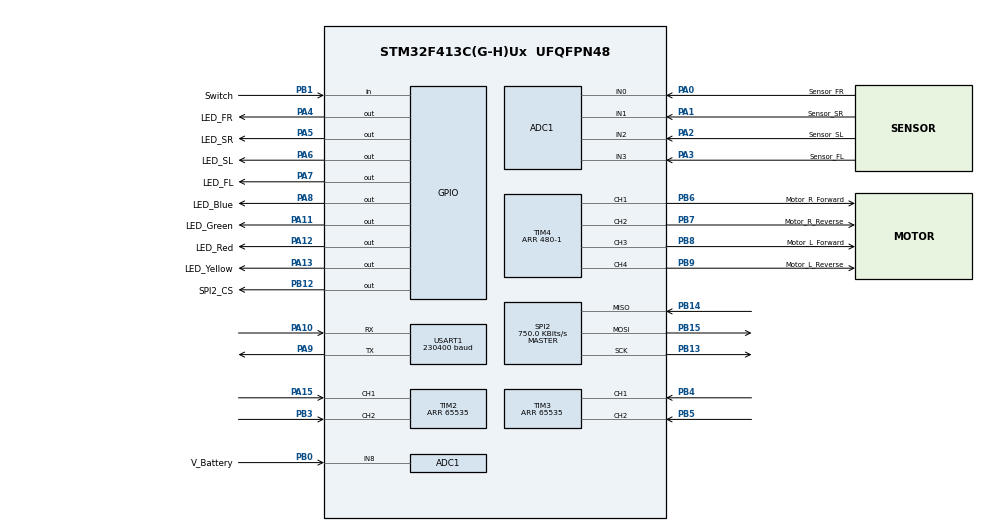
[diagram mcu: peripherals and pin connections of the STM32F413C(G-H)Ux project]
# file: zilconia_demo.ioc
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ADC1.Channel-4\#ChannelRegularConversion=ADC_CHANNEL_8
ADC1.Channel-5\#ChannelRegularConversion=ADC_CHANNEL_0
ADC1.Channel-6\#ChannelRegularConversion=ADC_CHANNEL_1
ADC1.Channel-7\#ChannelRegularConversion=ADC_CHANNEL_2
ADC1.Channel-8\#ChannelRegularConversion=ADC_CHANNEL_3
ADC1.ClockPrescaler=ADC_CLOCK_SYNC_PCLK_DIV4
ADC1.DMAContinuousRequests=ENABLE
ADC1.EOCSelection=ADC_EOC_SEQ_CONV
ADC1.ExternalTrigConv=ADC_EXTERNALTRIGCONV_T1_CC3
ADC1.InjNumberOfConversion=0
ADC1.NbrOfConversion=5
ADC1.NbrOfConversionFlag=1
ADC1.Rank-4\#ChannelRegularConversion=1
ADC1.Rank-5\#ChannelRegularConversion=2
ADC1.Rank-6\#ChannelRegularConversion=3
ADC1.Rank-7\#ChannelRegularConversion=4
ADC1.Rank-8\#ChannelRegularConversion=5
ADC1.SamplingTime-4\#ChannelRegularConversion=ADC_SAMPLETIME_56CYCLES
ADC1.SamplingTime-5\#ChannelRegularConversion=ADC_SAMPLETIME_56CYCLES
ADC1.SamplingTime-6\#ChannelRegularConversion=ADC_SAMPLETIME_56CYCLES
ADC1.SamplingTime-7\#ChannelRegularConversion=ADC_SAMPLETIME_56CYCLES
ADC1.SamplingTime-8\#ChannelRegularConversion=ADC_SAMPLETIME_56CYCLES
ADC1.ScanConvMode=ENABLE
ADC1.master=1
Dma.ADC1.0.Direction=DMA_PERIPH_TO_MEMORY
Dma.ADC1.0.FIFOMode=DMA_FIFOMODE_DISABLE
Dma.ADC1.0.Instance=DMA2_Stream0
Dma.ADC1.0.MemDataAlignment=DMA_MDATAALIGN_HALFWORD
Dma.ADC1.0.MemInc=DMA_MINC_ENABLE
Dma.ADC1.0.Mode=DMA_CIRCULAR
Dma.ADC1.0.PeriphDataAlignment=DMA_PDATAALIGN_HALFWORD
Dma.ADC1.0.PeriphInc=DMA_PINC_DISABLE
Dma.ADC1.0.Priority=DMA_PRIORITY_VERY_HIGH
Dma.Request0=ADC1
Dma.Request1=SPI2_RX
Dma.Request2=SPI2_TX
Dma.Request3=TIM1_CH1
Dma.Request4=TIM1_CH2
Dma.Request5=USART1_RX
Dma.Request6=USART1_TX
Dma.SPI2_RX.1.Direction=DMA_PERIPH_TO_MEMORY
Dma.SPI2_RX.1.FIFOMode=DMA_FIFOMODE_DISABLE
Dma.SPI2_RX.1.Instance=DMA1_Stream3
Dma.SPI2_RX.1.MemDataAlignment=DMA_MDATAALIGN_BYTE
Dma.SPI2_RX.1.MemInc=DMA_MINC_ENABLE
Dma.SPI2_RX.1.Mode=DMA_NORMAL
Dma.SPI2_RX.1.PeriphDataAlignment=DMA_PDATAALIGN_BYTE
Dma.SPI2_RX.1.PeriphInc=DMA_PINC_DISABLE
Dma.SPI2_RX.1.Priority=DMA_PRIORITY_VERY_HIGH
Dma.SPI2_TX.2.Direction=DMA_MEMORY_TO_PERIPH
Dma.SPI2_TX.2.FIFOMode=DMA_FIFOMODE_DISABLE
Dma.SPI2_TX.2.Instance=DMA1_Stream4
Dma.SPI2_TX.2.MemDataAlignment=DMA_MDATAALIGN_BYTE
Dma.SPI2_TX.2.MemInc=DMA_MINC_ENABLE
Dma.SPI2_TX.2.Mode=DMA_NORMAL
Dma.SPI2_TX.2.PeriphDataAlignment=DMA_PDATAALIGN_BYTE
Dma.SPI2_TX.2.PeriphInc=DMA_PINC_DISABLE
Dma.SPI2_TX.2.Priority=DMA_PRIORITY_VERY_HIGH
Dma.TIM1_CH1.3.Direction=DMA_MEMORY_TO_PERIPH
Dma.TIM1_CH1.3.FIFOMode=DMA_FIFOMODE_DISABLE
Dma.TIM1_CH1.3.Instance=DMA2_Stream1
Dma.TIM1_CH1.3.MemDataAlignment=DMA_MDATAALIGN_HALFWORD
Dma.TIM1_CH1.3.MemInc=DMA_MINC_ENABLE
Dma.TIM1_CH1.3.Mode=DMA_CIRCULAR
Dma.TIM1_CH1.3.PeriphDataAlignment=DMA_PDATAALIGN_HALFWORD
Dma.TIM1_CH1.3.PeriphInc=DMA_PINC_DISABLE
Dma.TIM1_CH1.3.Priority=DMA_PRIORITY_VERY_HIGH
Dma.TIM1_CH2.4.Direction=DMA_MEMORY_TO_PERIPH
Dma.TIM1_CH2.4.FIFOMode=DMA_FIFOMODE_DISABLE
Dma.TIM1_CH2.4.Instance=DMA2_Stream2
Dma.TIM1_CH2.4.MemDataAlignment=DMA_MDATAALIGN_HALFWORD
Dma.TIM1_CH2.4.MemInc=DMA_MINC_ENABLE
Dma.TIM1_CH2.4.Mode=DMA_CIRCULAR
Dma.TIM1_CH2.4.PeriphDataAlignment=DMA_PDATAALIGN_HALFWORD
Dma.TIM1_CH2.4.PeriphInc=DMA_PINC_DISABLE
Dma.TIM1_CH2.4.Priority=DMA_PRIORITY_VERY_HIGH
Dma.USART1_RX.5.Direction=DMA_PERIPH_TO_MEMORY
Dma.USART1_RX.5.FIFOMode=DMA_FIFOMODE_DISABLE
Dma.USART1_RX.5.Instance=DMA2_Stream5
Dma.USART1_RX.5.MemDataAlignment=DMA_MDATAALIGN_BYTE
Dma.USART1_RX.5.MemInc=DMA_MINC_ENABLE
Dma.USART1_RX.5.Mode=DMA_CIRCULAR
Dma.USART1_RX.5.PeriphDataAlignment=DMA_PDATAALIGN_BYTE
Dma.USART1_RX.5.PeriphInc=DMA_PINC_DISABLE
Dma.USART1_RX.5.Priority=DMA_PRIORITY_LOW
Dma.USART1_TX.6.Direction=DMA_MEMORY_TO_PERIPH
Dma.USART1_TX.6.FIFOMode=DMA_FIFOMODE_DISABLE
Dma.USART1_TX.6.Instance=DMA2_Stream7
Dma.USART1_TX.6.MemDataAlignment=DMA_MDATAALIGN_BYTE
Dma.USART1_TX.6.MemInc=DMA_MINC_ENABLE
Dma.USART1_TX.6.Mode=DMA_NORMAL
Dma.USART1_TX.6.PeriphDataAlignment=DMA_PDATAALIGN_BYTE
Dma.USART1_TX.6.PeriphInc=DMA_PINC_DISABLE
Dma.USART1_TX.6.Priority=DMA_PRIORITY_LOW
Mcu.Family=STM32F4
Mcu.Name=STM32F413C(G-H)Ux
Mcu.Package=UFQFPN48
NVIC.DMA1_Stream3_IRQn=true\:0\:0\:false\:false\:true\:false\:true
NVIC.DMA1_Stream4_IRQn=true\:0\:0\:false\:false\:true\:false\:true
NVIC.DMA2_Stream0_IRQn=true\:0\:0\:false\:false\:true\:false\:true
NVIC.DMA2_Stream1_IRQn=true\:0\:0\:false\:false\:true\:false\:true
NVIC.DMA2_Stream2_IRQn=true\:0\:0\:false\:false\:true\:false\:true
NVIC.DMA2_Stream5_IRQn=true\:2\:0\:true\:false\:true\:false\:true
NVIC.DMA2_Stream7_IRQn=true\:2\:0\:true\:false\:true\:false\:true
NVIC.PriorityGroup=NVIC_PRIORITYGROUP_4
NVIC.TIM6_DAC_IRQn=true\:1\:0\:true\:false\:true\:true\:true
NVIC.USART1_IRQn=true\:2\:0\:true\:false\:true\:true\:true
PA0.GPIO_Label=Sensor_FR
PA0.Signal=ADCx_IN0
PA1.GPIO_Label=Sensor_SR
PA1.Signal=ADCx_IN1
PA10.Mode=Asynchronous
PA10.Signal=USART1_RX
PA11.GPIO_Label=LED_Green
PA11.GPIO_Speed=GPIO_SPEED_FREQ_HIGH
PA11.Signal=GPIO_Output
PA12.GPIO_Label=LED_Red
PA12.GPIO_Speed=GPIO_SPEED_FREQ_HIGH
PA12.Signal=GPIO_Output
PA13.GPIO_Label=LED_Yellow
PA13.GPIO_Speed=GPIO_SPEED_FREQ_HIGH
PA13.Signal=GPIO_Output
PA15.Signal=S_TIM2_CH1_ETR
PA2.GPIO_Label=Sensor_SL
PA2.Signal=ADCx_IN2
PA3.GPIO_Label=Sensor_FL
PA3.Signal=ADCx_IN3
PA4.GPIO_Label=LED_FR
PA4.GPIO_Speed=GPIO_SPEED_FREQ_HIGH
PA4.Signal=GPIO_Output
PA5.GPIO_Label=LED_SR
PA5.GPIO_Speed=GPIO_SPEED_FREQ_HIGH
PA5.Signal=GPIO_Output
PA6.GPIO_Label=LED_SL
PA6.GPIO_Speed=GPIO_SPEED_FREQ_HIGH
PA6.Signal=GPIO_Output
PA7.GPIO_Label=LED_FL
PA7.GPIO_Speed=GPIO_SPEED_FREQ_HIGH
PA7.Signal=GPIO_Output
PA8.GPIO_Label=LED_Blue
PA8.GPIO_Speed=GPIO_SPEED_FREQ_HIGH
PA8.Signal=GPIO_Output
PA9.Mode=Asynchronous
PA9.Signal=USART1_TX
PB0.GPIO_Label=V_Battery
PB0.Signal=ADCx_IN8
PB1.GPIO_Label=Switch
PB1.Signal=GPIO_Input
PB12.GPIO_Label=SPI2_CS
PB12.GPIO_Speed=GPIO_SPEED_FREQ_VERY_HIGH
PB12.Signal=GPIO_Output
PB13.Mode=Full_Duplex_Master
PB13.Signal=SPI2_SCK
PB14.Mode=Full_Duplex_Master
PB14.Signal=SPI2_MISO
PB15.Mode=Full_Duplex_Master
PB15.Signal=SPI2_MOSI
PB3.Signal=S_TIM2_CH2
PB4.Signal=S_TIM3_CH1
PB5.Signal=S_TIM3_CH2
PB6.GPIO_Label=Motor_R_Forward
PB6.GPIO_Speed=GPIO_SPEED_FREQ_VERY_HIGH
PB6.Signal=S_TIM4_CH1
PB7.GPIO_Label=Motor_R_Reverse
PB7.GPIO_Speed=GPIO_SPEED_FREQ_VERY_HIGH
PB7.Signal=S_TIM4_CH2
PB8.GPIO_Label=Motor_L_Forward
PB8.GPIO_Speed=GPIO_SPEED_FREQ_VERY_HIGH
PB8.Signal=S_TIM4_CH3
PB9.GPIO_Label=Motor_L_Reverse
PB9.GPIO_Speed=GPIO_SPEED_FREQ_VERY_HIGH
PB9.Signal=S_TIM4_CH4
ProjectManager.HeapSize=0x200
ProjectManager.StackSize=0x400
ProjectManager.TargetToolchain=TrueSTUDIO
RCC.AHBFreq_Value=96000000
RCC.APB1CLKDivider=RCC_HCLK_DIV2
RCC.APB1Freq_Value=48000000
RCC.APB1TimFreq_Value=96000000
RCC.APB2Freq_Value=96000000
RCC.APB2TimFreq_Value=96000000
RCC.CortexFreq_Value=96000000
RCC.HCLKFreq_Value=96000000
RCC.SYSCLKFreq_VALUE=96000000
RCC.SYSCLKSource=RCC_SYSCLKSOURCE_PLLCLK
RCC.USBFreq_Value=96000000
RCC.VCOOutputFreq_Value=192000000
SH.ADCx_IN0.0=ADC1_IN0,IN0
SH.ADCx_IN1.0=ADC1_IN1,IN1
SH.ADCx_IN2.0=ADC1_IN2,IN2
SH.ADCx_IN3.0=ADC1_IN3,IN3
SH.ADCx_IN8.0=ADC1_IN8,IN8
SH.S_TIM2_CH1_ETR.0=TIM2_CH1,Encoder_Interface
SH.S_TIM2_CH2.0=TIM2_CH2,Encoder_Interface
SH.S_TIM3_CH1.0=TIM3_CH1,Encoder_Interface
SH.S_TIM3_CH2.0=TIM3_CH2,Encoder_Interface
SH.S_TIM4_CH1.0=TIM4_CH1,PWM Generation1 CH1
SH.S_TIM4_CH2.0=TIM4_CH2,PWM Generation2 CH2
SH.S_TIM4_CH3.0=TIM4_CH3,PWM Generation3 CH3
SH.S_TIM4_CH4.0=TIM4_CH4,PWM Generation4 CH4
SPI2.BaudRatePrescaler=SPI_BAUDRATEPRESCALER_64
SPI2.CLKPhase=SPI_PHASE_2EDGE
SPI2.CLKPolarity=SPI_POLARITY_HIGH
SPI2.CalculateBaudRate=750.0 KBits/s
SPI2.Direction=SPI_DIRECTION_2LINES
SPI2.Mode=SPI_MODE_MASTER
SPI2.VirtualType=VM_MASTER
TIM1.Channel-PWM\ Generation1\ No\ Output=TIM_CHANNEL_1
TIM1.Channel-PWM\ Generation2\ No\ Output=TIM_CHANNEL_2
TIM1.Channel-PWM\ Generation3\ No\ Output=TIM_CHANNEL_3
TIM1.OCMode_PWM-PWM\ Generation1\ No\ Output=TIM_OCMODE_PWM1
TIM1.OCMode_PWM-PWM\ Generation2\ No\ Output=TIM_OCMODE_PWM1
TIM1.OCMode_PWM-PWM\ Generation3\ No\ Output=TIM_OCMODE_PWM1
TIM1.Period=32000-1
TIM1.Pulse-PWM\ Generation1\ No\ Output=2-1
TIM1.Pulse-PWM\ Generation2\ No\ Output=2402-1
TIM1.Pulse-PWM\ Generation3\ No\ Output=1922-1
TIM1.TIM_MasterOutputTrigger=TIM_TRGO_RESET
TIM1.TIM_MasterSlaveMode=TIM_MASTERSLAVEMODE_DISABLE
TIM2.EncoderMode=TIM_ENCODERMODE_TI12
TIM2.Period=65535
TIM3.EncoderMode=TIM_ENCODERMODE_TI12
TIM3.Period=65535
TIM4.Channel-PWM\ Generation1\ CH1=TIM_CHANNEL_1
TIM4.Channel-PWM\ Generation2\ CH2=TIM_CHANNEL_2
TIM4.Channel-PWM\ Generation3\ CH3=TIM_CHANNEL_3
TIM4.Channel-PWM\ Generation4\ CH4=TIM_CHANNEL_4
TIM4.OCMode_PWM-PWM\ Generation1\ CH1=TIM_OCMODE_PWM2
TIM4.OCMode_PWM-PWM\ Generation2\ CH2=TIM_OCMODE_PWM2
TIM4.OCMode_PWM-PWM\ Generation3\ CH3=TIM_OCMODE_PWM2
TIM4.OCMode_PWM-PWM\ Generation4\ CH4=TIM_OCMODE_PWM2
TIM4.Period=480-1
TIM6.Period=24000
TIM6.Prescaler=4
USART1.BaudRate=230400
USART1.VirtualMode=VM_ASYNC
VP_TIM1_VS_ClockSourceINT.Mode=Internal
VP_TIM1_VS_no_output1.Mode=PWM Generation1 No Output
VP_TIM1_VS_no_output2.Mode=PWM Generation2 No Output
VP_TIM1_VS_no_output3.Mode=PWM Generation3 No Output
VP_TIM4_VS_ClockSourceINT.Mode=Internal
VP_TIM6_VS_ClockSourceINT.Mode=Enable_Timer
board=custom

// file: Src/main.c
/* USER CODE BEGIN Header */
/**
  ******************************************************************************
  * @file           : main.c
  * @brief          : Main program body
  ******************************************************************************
  ** This notice applies to any and all portions of this file
  * that are not between comment pairs USER CODE BEGIN and
  * USER CODE END. Other portions of this file, whether
  * inserted by the user or by software development tools
  * are owned by their respective copyright owners.
  *
  * COPYRIGHT(c) 2019 STMicroelectronics
  *
  * Redistribution and use in source and binary forms, with or without modification,
  * are permitted provided that the following conditions are met:
  *   1. Redistributions of source code must retain the above copyright notice,
  *      this list of conditions and the following disclaimer.
  *   2. Redistributions in binary form must reproduce the above copyright notice,
  *      this list of conditions and the following disclaimer in the documentation
  *      and/or other materials provided with the distribution.
  *   3. Neither the name of STMicroelectronics nor the names of its contributors
  *      may be used to endorse or promote products derived from this software
  *      without specific prior written permission.
  *
  * THIS SOFTWARE IS PROVIDED BY THE COPYRIGHT HOLDERS AND CONTRIBUTORS "AS IS"
  * AND ANY EXPRESS OR IMPLIED WARRANTIES, INCLUDING, BUT NOT LIMITED TO, THE
  * IMPLIED WARRANTIES OF MERCHANTABILITY AND FITNESS FOR A PARTICULAR PURPOSE ARE
  * DISCLAIMED. IN NO EVENT SHALL THE COPYRIGHT HOLDER OR CONTRIBUTORS BE LIABLE
  * FOR ANY DIRECT, INDIRECT, INCIDENTAL, SPECIAL, EXEMPLARY, OR CONSEQUENTIAL
  * DAMAGES (INCLUDING, BUT NOT LIMITED TO, PROCUREMENT OF SUBSTITUTE GOODS OR
  * SERVICES; LOSS OF USE, DATA, OR PROFITS; OR BUSINESS INTERRUPTION) HOWEVER
  * CAUSED AND ON ANY THEORY OF LIABILITY, WHETHER IN CONTRACT, STRICT LIABILITY,
  * OR TORT (INCLUDING NEGLIGENCE OR OTHERWISE) ARISING IN ANY WAY OUT OF THE USE
  * OF THIS SOFTWARE, EVEN IF ADVISED OF THE POSSIBILITY OF SUCH DAMAGE.
  *
  ******************************************************************************
  */
/* USER CODE END Header */

#include "main.h"
#include "adc.h"
#include "dma.h"
#include "spi.h"
#include "tim.h"
#include "usart.h"
#include "gpio.h"

/* USER CODE BEGIN Includes */
#include "index.h"
/* USER CODE END Includes */

void SystemClock_Config(void);

int main(void)
{

  /* MCU Configuration--------------------------------------------------------*/

  /* Reset of all peripherals, Initializes the Flash interface and the Systick. */
  HAL_Init();

  /* Configure the system clock */
  SystemClock_Config();

  /* Initialize all configured peripherals */
  MX_GPIO_Init();
  MX_DMA_Init();
  MX_USART1_UART_Init();
  MX_SPI2_Init();
  MX_ADC1_Init();
  MX_TIM2_Init();
  MX_TIM3_Init();
  MX_TIM4_Init();
  MX_TIM1_Init();
  MX_TIM6_Init();
  /* USER CODE BEGIN 2 */
  	LED_ALL_ON();				// LED全点灯
  	Communication_Initialize();	// ターミナルとの通信設定
  	Motor_Initialize();			// モータ用タイマー設定
  	Encoder_Initialize();		// エンコーダ用タイマー設定
  	IMU_Initialize();			// IMU用通信およびICM20648の初期設定
  	Sensor_Initialize();		// 壁センサ用AD変換およびタイマー設定
  	Interrupt_Initialize();		// メイン割り込み処理の初期設定
  	Battery_LimiterVoltage();	// バッテリーの電圧管理

  	module_test();				// 各機能の動作確認（動作確認が完了したらコメントアウトして下さい）
  /* USER CODE END 2 */

  /* Infinite loop */
  while (1)
  {

    /* USER CODE BEGIN 3 */
	  // ここにメインループの処理を記述する

  }
  /* USER CODE END 3 */
}

void SystemClock_Config(void)
{
  RCC_OscInitTypeDef RCC_OscInitStruct = {0};
  RCC_ClkInitTypeDef RCC_ClkInitStruct = {0};

  /** Configure the main internal regulator output voltage
  */
  __HAL_RCC_PWR_CLK_ENABLE();
  __HAL_PWR_VOLTAGESCALING_CONFIG(PWR_REGULATOR_VOLTAGE_SCALE1);
  /** Initializes the CPU, AHB and APB busses clocks
  */
  RCC_OscInitStruct.OscillatorType = RCC_OSCILLATORTYPE_HSI;
  RCC_OscInitStruct.HSIState = RCC_HSI_ON;
  RCC_OscInitStruct.HSICalibrationValue = RCC_HSICALIBRATION_DEFAULT;
  RCC_OscInitStruct.PLL.PLLState = RCC_PLL_ON;
  RCC_OscInitStruct.PLL.PLLSource = RCC_PLLSOURCE_HSI;
  RCC_OscInitStruct.PLL.PLLM = 16;
  RCC_OscInitStruct.PLL.PLLN = 192;
  RCC_OscInitStruct.PLL.PLLP = RCC_PLLP_DIV2;
  RCC_OscInitStruct.PLL.PLLQ = 2;
  RCC_OscInitStruct.PLL.PLLR = 2;
  if (HAL_RCC_OscConfig(&RCC_OscInitStruct) != HAL_OK)
  {
    Error_Handler();
  }
  /** Initializes the CPU, AHB and APB busses clocks
  */
  RCC_ClkInitStruct.ClockType = RCC_CLOCKTYPE_HCLK|RCC_CLOCKTYPE_SYSCLK
                              |RCC_CLOCKTYPE_PCLK1|RCC_CLOCKTYPE_PCLK2;
  RCC_ClkInitStruct.SYSCLKSource = RCC_SYSCLKSOURCE_PLLCLK;
  RCC_ClkInitStruct.AHBCLKDivider = RCC_SYSCLK_DIV1;
  RCC_ClkInitStruct.APB1CLKDivider = RCC_HCLK_DIV1;
  RCC_ClkInitStruct.APB2CLKDivider = RCC_HCLK_DIV2;

  if (HAL_RCC_ClockConfig(&RCC_ClkInitStruct, FLASH_LATENCY_3) != HAL_OK)
  {
    Error_Handler();
  }
}

void Error_Handler(void)
{
}

/************************ (C) COPYRIGHT STMicroelectronics *****END OF FILE****/
